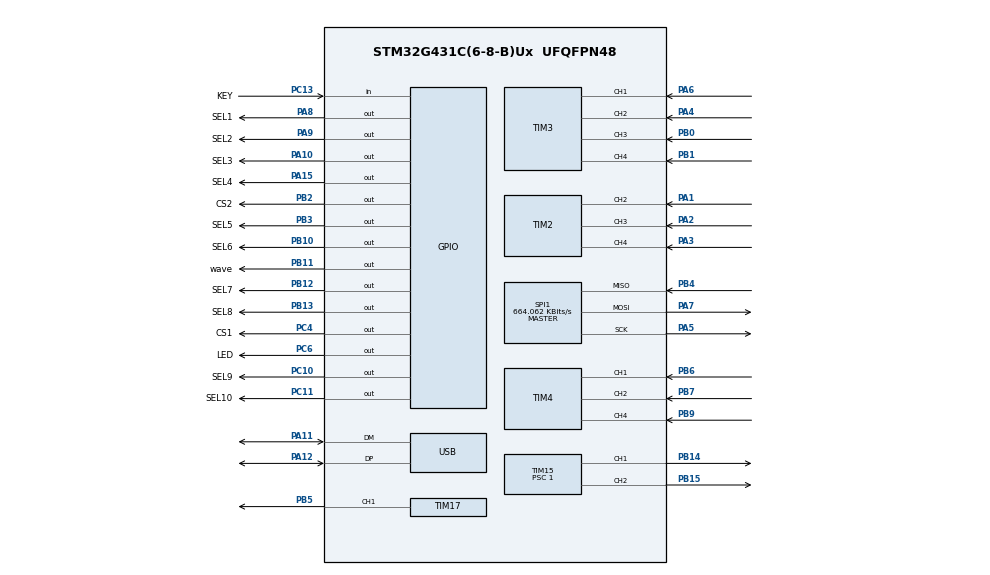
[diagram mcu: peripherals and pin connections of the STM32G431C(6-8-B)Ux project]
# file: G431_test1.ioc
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FREERTOS.BinarySemaphores01=usbBinarySem,Dynamic,NULL
FREERTOS.INCLUDE_uxTaskGetStackHighWaterMark=1
FREERTOS.INCLUDE_vTaskDelayUntil=1
FREERTOS.Queues01=Line1Queue,20,uint16_t,0,Dynamic,NULL,NULL;Line2Queue,20,uint16_t,0,Dynamic,NULL,NULL;Line3Queue,20,uint16_t,0,Dynamic,NULL,NULL;Line4Queue,20,uint16_t,0,Dynamic,NULL,NULL;Line5Queue,20,uint16_t,0,Dynamic,NULL,NULL;Line6Queue,20,uint16_t,0,Dynamic,NULL,NULL;Line7Queue,20,uint16_t,0,Dynamic,NULL,NULL;Line8Queue,100,uint16_t,0,Dynamic,NULL,NULL;Line9Queue,100,uint16_t,0,Dynamic,NULL,NULL;Line10Queue,100,uint16_t,0,Dynamic,NULL,NULL
FREERTOS.Tasks01=defaultTask,0,1024,StartDefaultTask,Default,NULL,Dynamic,NULL,NULL;notifyTask,3,128,NotifyTask,Default,NULL,Dynamic,NULL,NULL;dataTask,-1,128,DataTask,Default,NULL,Dynamic,NULL,NULL
FREERTOS.configTOTAL_HEAP_SIZE=10240
Mcu.Family=STM32G4
Mcu.Name=STM32G431C(6-8-B)Ux
Mcu.Package=UFQFPN48
NVIC.PriorityGroup=NVIC_PRIORITYGROUP_4
NVIC.TIM2_IRQn=true\:5\:0\:false\:true\:false\:4\:true\:true\:false\:true
NVIC.TIM3_IRQn=true\:5\:0\:false\:true\:false\:3\:true\:true\:false\:true
NVIC.TIM4_IRQn=true\:5\:0\:false\:true\:false\:2\:true\:true\:false\:true
NVIC.TIM6_DAC_IRQn=true\:15\:0\:false\:false\:true\:false\:false\:true\:true
NVIC.TIM7_IRQn=true\:5\:0\:true\:true\:false\:1\:true\:true\:false\:true
NVIC.TimeBase=TIM6_DAC_IRQn
NVIC.TimeBaseIP=TIM6
NVIC.USB_LP_IRQn=true\:5\:0\:false\:false\:true\:true\:false\:true\:true
PA1.GPIO_PuPd=GPIO_PULLUP
PA1.GPIO_Speed=GPIO_SPEED_FREQ_VERY_HIGH
PA1.Signal=S_TIM2_CH2
PA10.GPIO_Label=SEL3
PA10.GPIO_ModeDefaultOutputPP=GPIO_MODE_OUTPUT_PP
PA10.GPIO_PuPd=GPIO_PULLUP
PA10.GPIO_Speed=GPIO_SPEED_FREQ_VERY_HIGH
PA10.PinState=GPIO_PIN_SET
PA10.Signal=GPIO_Output
PA11.Mode=Device
PA11.Signal=USB_DM
PA12.Mode=Device
PA12.Signal=USB_DP
PA13.Mode=Serial_Wire
PA13.Signal=SYS_JTMS-SWDIO
PA14.Mode=Serial_Wire
PA14.Signal=SYS_JTCK-SWCLK
PA15.GPIO_Label=SEL4
PA15.GPIO_ModeDefaultOutputPP=GPIO_MODE_OUTPUT_PP
PA15.GPIO_PuPd=GPIO_PULLUP
PA15.GPIO_Speed=GPIO_SPEED_FREQ_VERY_HIGH
PA15.PinState=GPIO_PIN_SET
PA15.Signal=GPIO_Output
PA2.GPIO_PuPd=GPIO_PULLUP
PA2.GPIO_Speed=GPIO_SPEED_FREQ_VERY_HIGH
PA2.Signal=S_TIM2_CH3
PA3.GPIO_PuPd=GPIO_PULLUP
PA3.GPIO_Speed=GPIO_SPEED_FREQ_VERY_HIGH
PA3.Signal=S_TIM2_CH4
PA4.GPIO_PuPd=GPIO_PULLUP
PA4.GPIO_Speed=GPIO_SPEED_FREQ_VERY_HIGH
PA4.Signal=S_TIM3_CH2
PA5.Mode=Full_Duplex_Master
PA5.Signal=SPI1_SCK
PA6.GPIO_PuPd=GPIO_PULLUP
PA6.GPIO_Speed=GPIO_SPEED_FREQ_VERY_HIGH
PA6.Signal=S_TIM3_CH1
PA7.Mode=Full_Duplex_Master
PA7.Signal=SPI1_MOSI
PA8.GPIO_Label=SEL1
PA8.GPIO_ModeDefaultOutputPP=GPIO_MODE_OUTPUT_PP
PA8.GPIO_PuPd=GPIO_PULLUP
PA8.GPIO_Speed=GPIO_SPEED_FREQ_VERY_HIGH
PA8.PinState=GPIO_PIN_SET
PA8.Signal=GPIO_Output
PA9.GPIO_Label=SEL2
PA9.GPIO_ModeDefaultOutputPP=GPIO_MODE_OUTPUT_PP
PA9.GPIO_PuPd=GPIO_PULLUP
PA9.GPIO_Speed=GPIO_SPEED_FREQ_VERY_HIGH
PA9.PinState=GPIO_PIN_SET
PA9.Signal=GPIO_Output
PB0.GPIO_PuPd=GPIO_PULLUP
PB0.GPIO_Speed=GPIO_SPEED_FREQ_VERY_HIGH
PB0.Signal=S_TIM3_CH3
PB1.GPIO_PuPd=GPIO_PULLUP
PB1.GPIO_Speed=GPIO_SPEED_FREQ_VERY_HIGH
PB1.Signal=S_TIM3_CH4
PB10.GPIO_Label=SEL6
PB10.GPIO_ModeDefaultOutputPP=GPIO_MODE_OUTPUT_PP
PB10.GPIO_PuPd=GPIO_PULLUP
PB10.GPIO_Speed=GPIO_SPEED_FREQ_VERY_HIGH
PB10.PinState=GPIO_PIN_SET
PB10.Signal=GPIO_Output
PB11.GPIO_Label=wave
PB11.GPIO_PuPd=GPIO_PULLDOWN
PB11.GPIO_Speed=GPIO_SPEED_FREQ_VERY_HIGH
PB11.Signal=GPIO_Output
PB12.GPIO_Label=SEL7
PB12.GPIO_ModeDefaultOutputPP=GPIO_MODE_OUTPUT_PP
PB12.GPIO_PuPd=GPIO_PULLUP
PB12.GPIO_Speed=GPIO_SPEED_FREQ_VERY_HIGH
PB12.PinState=GPIO_PIN_SET
PB12.Signal=GPIO_Output
PB13.GPIO_Label=SEL8
PB13.GPIO_ModeDefaultOutputPP=GPIO_MODE_OUTPUT_PP
PB13.GPIO_PuPd=GPIO_PULLUP
PB13.GPIO_Speed=GPIO_SPEED_FREQ_VERY_HIGH
PB13.PinState=GPIO_PIN_SET
PB13.Signal=GPIO_Output
PB14.GPIO_PuPd=GPIO_PULLUP
PB14.GPIO_Speed=GPIO_SPEED_FREQ_VERY_HIGH
PB14.Signal=S_TIM15_CH1
PB15.Signal=S_TIM15_CH2
PB2.GPIO_Label=CS2
PB2.GPIO_PuPd=GPIO_PULLUP
PB2.GPIO_Speed=GPIO_SPEED_FREQ_VERY_HIGH
PB2.PinState=GPIO_PIN_SET
PB2.Signal=GPIO_Output
PB3.GPIO_Label=SEL5
PB3.GPIO_ModeDefaultOutputPP=GPIO_MODE_OUTPUT_PP
PB3.GPIO_PuPd=GPIO_PULLUP
PB3.GPIO_Speed=GPIO_SPEED_FREQ_VERY_HIGH
PB3.PinState=GPIO_PIN_SET
PB3.Signal=GPIO_Output
PB4.Mode=Full_Duplex_Master
PB4.Signal=SPI1_MISO
PB5.GPIO_PuPd=GPIO_NOPULL
PB5.GPIO_Speed=GPIO_SPEED_FREQ_VERY_HIGH
PB5.Signal=S_TIM17_CH1
PB6.GPIO_PuPd=GPIO_PULLUP
PB6.GPIO_Speed=GPIO_SPEED_FREQ_VERY_HIGH
PB6.Signal=S_TIM4_CH1
PB7.GPIO_PuPd=GPIO_PULLUP
PB7.GPIO_Speed=GPIO_SPEED_FREQ_VERY_HIGH
PB7.Signal=S_TIM4_CH2
PB9.GPIO_PuPd=GPIO_PULLUP
PB9.GPIO_Speed=GPIO_SPEED_FREQ_VERY_HIGH
PB9.Signal=S_TIM4_CH4
PC10.GPIO_Label=SEL9
PC10.GPIO_ModeDefaultOutputPP=GPIO_MODE_OUTPUT_PP
PC10.GPIO_PuPd=GPIO_PULLUP
PC10.GPIO_Speed=GPIO_SPEED_FREQ_VERY_HIGH
PC10.PinState=GPIO_PIN_SET
PC10.Signal=GPIO_Output
PC11.GPIO_Label=SEL10
PC11.GPIO_ModeDefaultOutputPP=GPIO_MODE_OUTPUT_PP
PC11.GPIO_PuPd=GPIO_PULLUP
PC11.GPIO_Speed=GPIO_SPEED_FREQ_VERY_HIGH
PC11.PinState=GPIO_PIN_SET
PC11.Signal=GPIO_Output
PC13.GPIO_Label=KEY
PC13.GPIO_PuPd=GPIO_PULLDOWN
PC13.Signal=GPIO_Input
PC4.GPIO_Label=CS1
PC4.GPIO_PuPd=GPIO_PULLUP
PC4.GPIO_Speed=GPIO_SPEED_FREQ_VERY_HIGH
PC4.PinState=GPIO_PIN_SET
PC4.Signal=GPIO_Output
PC6.GPIO_Label=LED
PC6.GPIO_PuPd=GPIO_PULLUP
PC6.GPIO_Speed=GPIO_SPEED_FREQ_VERY_HIGH
PC6.PinState=GPIO_PIN_RESET
PC6.Signal=GPIO_Output
PF0-OSC_IN.Mode=HSE-External-Oscillator
PF0-OSC_IN.Signal=RCC_OSC_IN
PF1-OSC_OUT.Mode=HSE-External-Oscillator
PF1-OSC_OUT.Signal=RCC_OSC_OUT
ProjectManager.HeapSize=0x100
ProjectManager.StackSize=0x1000
ProjectManager.TargetToolchain=MDK-ARM V5.32
RCC.ADC12Freq_Value=170000000
RCC.AHBFreq_Value=170000000
RCC.APB1Freq_Value=170000000
RCC.APB1TimFreq_Value=170000000
RCC.APB2Freq_Value=170000000
RCC.APB2TimFreq_Value=170000000
RCC.CK48CLockSelection=RCC_USBCLKSOURCE_HSI48
RCC.CortexFreq_Value=170000000
RCC.EXTERNAL_CLOCK_VALUE=12288000
RCC.HCLKFreq_Value=170000000
RCC.HSE_VALUE=8000000
RCC.HSI48_VALUE=48000000
RCC.HSI_VALUE=16000000
RCC.LSE_VALUE=32768
RCC.PLLM=RCC_PLLM_DIV2
RCC.PLLN=85
RCC.PLLSourceVirtual=RCC_PLLSOURCE_HSE
RCC.SYSCLKFreq_VALUE=170000000
RCC.SYSCLKSource=RCC_SYSCLKSOURCE_PLLCLK
RCC.USBFreq_Value=48000000
RCC.VCOOutputFreq_Value=340000000
SH.S_TIM15_CH1.0=TIM15_CH1,PWM Generation1 CH1
SH.S_TIM15_CH2.0=TIM15_CH2,PWM Generation2 CH2
SH.S_TIM17_CH1.0=TIM17_CH1,PWM Generation1 CH1
SH.S_TIM2_CH2.0=TIM2_CH2,Input_Capture2_from_TI2
SH.S_TIM2_CH3.0=TIM2_CH3,Input_Capture3_from_TI3
SH.S_TIM2_CH4.0=TIM2_CH4,Input_Capture4_from_TI4
SH.S_TIM3_CH1.0=TIM3_CH1,Input_Capture1_from_TI1
SH.S_TIM3_CH2.0=TIM3_CH2,Input_Capture2_from_TI2
SH.S_TIM3_CH3.0=TIM3_CH3,Input_Capture3_from_TI3
SH.S_TIM3_CH4.0=TIM3_CH4,Input_Capture4_from_TI4
SH.S_TIM4_CH1.0=TIM4_CH1,Input_Capture1_from_TI1
SH.S_TIM4_CH2.0=TIM4_CH2,Input_Capture2_from_TI2
SH.S_TIM4_CH4.0=TIM4_CH4,Input_Capture4_from_TI4
SPI1.BaudRatePrescaler=SPI_BAUDRATEPRESCALER_256
SPI1.CalculateBaudRate=664.062 KBits/s
SPI1.DataSize=SPI_DATASIZE_8BIT
SPI1.Direction=SPI_DIRECTION_2LINES
SPI1.Mode=SPI_MODE_MASTER
SPI1.VirtualType=VM_MASTER
TIM15.Channel-PWM\ Generation1\ CH1=TIM_CHANNEL_1
TIM15.Channel-PWM\ Generation2\ CH2=TIM_CHANNEL_2
TIM15.OCPolarity_1=TIM_OCPOLARITY_LOW
TIM15.OCPolarity_2=TIM_OCPOLARITY_LOW
TIM15.PeriodNoDither=9999
TIM15.Prescaler=1
TIM17.Channel=TIM_CHANNEL_1
TIM17.OCIdleState_1=TIM_OCIDLESTATE_SET
TIM17.OCPolarity_1=TIM_OCPOLARITY_HIGH
TIM17.PeriodNoDither=4999
TIM17.Prescaler=1
TIM17.PulseNoDither_1=450
TIM2.Channel-Input_Capture2_from_TI2=TIM_CHANNEL_2
TIM2.Channel-Input_Capture3_from_TI3=TIM_CHANNEL_3
TIM2.Channel-Input_Capture4_from_TI4=TIM_CHANNEL_4
TIM2.ICFilter_CH2=2
TIM2.ICFilter_CH3=2
TIM2.ICFilter_CH4=2
TIM2.ICPolarity_CH2=TIM_INPUTCHANNELPOLARITY_FALLING
TIM2.ICPolarity_CH3=TIM_INPUTCHANNELPOLARITY_FALLING
TIM2.ICPolarity_CH4=TIM_INPUTCHANNELPOLARITY_FALLING
TIM3.Channel-Input_Capture1_from_TI1=TIM_CHANNEL_1
TIM3.Channel-Input_Capture2_from_TI2=TIM_CHANNEL_2
TIM3.Channel-Input_Capture3_from_TI3=TIM_CHANNEL_3
TIM3.Channel-Input_Capture4_from_TI4=TIM_CHANNEL_4
TIM3.ICFilter_CH1=2
TIM3.ICFilter_CH2=2
TIM3.ICFilter_CH3=2
TIM3.ICFilter_CH4=2
TIM3.ICPolarity_CH1=TIM_INPUTCHANNELPOLARITY_FALLING
TIM3.ICPolarity_CH2=TIM_INPUTCHANNELPOLARITY_FALLING
TIM3.ICPolarity_CH3=TIM_INPUTCHANNELPOLARITY_FALLING
TIM3.ICPolarity_CH4=TIM_INPUTCHANNELPOLARITY_FALLING
TIM4.Channel-Input_Capture1_from_TI1=TIM_CHANNEL_1
TIM4.Channel-Input_Capture2_from_TI2=TIM_CHANNEL_2
TIM4.Channel-Input_Capture4_from_TI4=TIM_CHANNEL_4
TIM4.ICFilter_CH1=2
TIM4.ICFilter_CH2=2
TIM4.ICFilter_CH4=2
TIM4.ICPolarity_CH1=TIM_INPUTCHANNELPOLARITY_FALLING
TIM4.ICPolarity_CH2=TIM_INPUTCHANNELPOLARITY_FALLING
TIM4.ICPolarity_CH4=TIM_INPUTCHANNELPOLARITY_FALLING
TIM7.PeriodNoDither=65535
TIM7.Prescaler=199
USB_DEVICE.CLASS_NAME_FS=CDC
USB_DEVICE.VirtualMode=Cdc
USB_DEVICE.VirtualModeFS=Cdc_FS
VP_FREERTOS_VS_CMSIS_V1.Mode=CMSIS_V1
VP_SYS_VS_DBSignals.Mode=DisableDeadBatterySignals
VP_SYS_VS_tim6.Mode=TIM6
VP_TIM17_VS_ClockSourceINT.Mode=Enable_Timer
VP_TIM17_VS_OPM.Mode=OPM_bit
VP_TIM7_VS_ClockSourceINT.Mode=Enable_Timer
VP_USB_DEVICE_VS_USB_DEVICE_CDC_FS.Mode=CDC_FS
board=custom

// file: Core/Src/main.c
/* USER CODE BEGIN Header */
/**
  ******************************************************************************
  * @file           : main.c
  * @brief          : Main program body
  ******************************************************************************
  * @attention
  *
  * Copyright (c) 2024 STMicroelectronics.
  * All rights reserved.
  *
  * This software is licensed under terms that can be found in the LICENSE file
  * in the root directory of this software component.
  * If no LICENSE file comes with this software, it is provided AS-IS.
  *
  ******************************************************************************
  */
/* USER CODE END Header */
#include "main.h"
#include "cmsis_os.h"
#include "spi.h"
#include "tim.h"
#include "usb_device.h"
#include "gpio.h"

void SystemClock_Config(void);
void MX_FREERTOS_Init(void);
static void MX_NVIC_Init(void);

int main(void)
{

  /* MCU Configuration--------------------------------------------------------*/

  /* Reset of all peripherals, Initializes the Flash interface and the Systick. */
  HAL_Init();

  /* Configure the system clock */
  SystemClock_Config();

  /* Initialize all configured peripherals */
  MX_GPIO_Init();
  MX_USB_Device_Init();
  MX_TIM7_Init();
  MX_TIM2_Init();
  MX_TIM3_Init();
  MX_TIM4_Init();
  MX_SPI1_Init();
  MX_TIM15_Init();
  MX_TIM17_Init();

  /* Initialize interrupts */
  MX_NVIC_Init();
  /* USER CODE BEGIN 2 */
	LL_TIM_EnableIT_UPDATE(TIM7);//start TIM7 IRQ
	LL_TIM_EnableCounter(TIM7);//start TIM7

	LL_TIM_EnableIT_UPDATE(TIM3);
	LL_TIM_EnableIT_CC1(TIM3);
	LL_TIM_EnableIT_CC2(TIM3);
	LL_TIM_EnableIT_CC3(TIM3);
	LL_TIM_EnableIT_CC4(TIM3);
	LL_TIM_CC_EnableChannel(TIM3,LL_TIM_CHANNEL_CH1);
	LL_TIM_CC_EnableChannel(TIM3,LL_TIM_CHANNEL_CH2);
	LL_TIM_CC_EnableChannel(TIM3,LL_TIM_CHANNEL_CH3);
	LL_TIM_CC_EnableChannel(TIM3,LL_TIM_CHANNEL_CH4);
	LL_TIM_EnableCounter(TIM3);

	LL_TIM_EnableIT_UPDATE(TIM4);
	LL_TIM_EnableIT_CC1(TIM4);
	LL_TIM_EnableIT_CC2(TIM4);
	LL_TIM_EnableIT_CC4(TIM4);
	LL_TIM_CC_EnableChannel(TIM4,LL_TIM_CHANNEL_CH1);
	LL_TIM_CC_EnableChannel(TIM4,LL_TIM_CHANNEL_CH2);
	LL_TIM_CC_EnableChannel(TIM4,LL_TIM_CHANNEL_CH4);
	LL_TIM_EnableCounter(TIM4);

	LL_TIM_EnableIT_UPDATE(TIM2);
	LL_TIM_EnableIT_CC2(TIM2);
	LL_TIM_EnableIT_CC3(TIM2);
	LL_TIM_EnableIT_CC4(TIM2);
	LL_TIM_CC_EnableChannel(TIM2,LL_TIM_CHANNEL_CH2);
	LL_TIM_CC_EnableChannel(TIM2,LL_TIM_CHANNEL_CH3);
	LL_TIM_CC_EnableChannel(TIM2,LL_TIM_CHANNEL_CH4);
	LL_TIM_EnableCounter(TIM2);

//		LL_GPIO_SetOutputPin(SEL1_GPIO_Port,SEL1_Pin);
//		LL_GPIO_ResetOutputPin(SEL1_GPIO_Port,SEL1_Pin);
  /* USER CODE END 2 */

  /* Call init function for freertos objects (in freertos.c) */
  MX_FREERTOS_Init();

  /* Start scheduler */
  osKernelStart();

  /* We should never get here as control is now taken by the scheduler */
  /* Infinite loop */
  while (1)
  {

  }
}

void SystemClock_Config(void)
{
  RCC_OscInitTypeDef RCC_OscInitStruct = {0};
  RCC_ClkInitTypeDef RCC_ClkInitStruct = {0};

  /** Configure the main internal regulator output voltage
  */
  HAL_PWREx_ControlVoltageScaling(PWR_REGULATOR_VOLTAGE_SCALE1_BOOST);

  /** Initializes the RCC Oscillators according to the specified parameters
  * in the RCC_OscInitTypeDef structure.
  */
  RCC_OscInitStruct.OscillatorType = RCC_OSCILLATORTYPE_HSI48|RCC_OSCILLATORTYPE_HSE;
  RCC_OscInitStruct.HSEState = RCC_HSE_ON;
  RCC_OscInitStruct.HSI48State = RCC_HSI48_ON;
  RCC_OscInitStruct.PLL.PLLState = RCC_PLL_ON;
  RCC_OscInitStruct.PLL.PLLSource = RCC_PLLSOURCE_HSE;
  RCC_OscInitStruct.PLL.PLLM = RCC_PLLM_DIV2;
  RCC_OscInitStruct.PLL.PLLN = 100;
  RCC_OscInitStruct.PLL.PLLP = RCC_PLLP_DIV2;
  RCC_OscInitStruct.PLL.PLLQ = RCC_PLLQ_DIV2;
  RCC_OscInitStruct.PLL.PLLR = RCC_PLLR_DIV2;
  if (HAL_RCC_OscConfig(&RCC_OscInitStruct) != HAL_OK)
  {
    Error_Handler();
  }

  /** Initializes the CPU, AHB and APB buses clocks
  */
  RCC_ClkInitStruct.ClockType = RCC_CLOCKTYPE_HCLK|RCC_CLOCKTYPE_SYSCLK
                              |RCC_CLOCKTYPE_PCLK1|RCC_CLOCKTYPE_PCLK2;
  RCC_ClkInitStruct.SYSCLKSource = RCC_SYSCLKSOURCE_PLLCLK;
  RCC_ClkInitStruct.AHBCLKDivider = RCC_SYSCLK_DIV1;
  RCC_ClkInitStruct.APB1CLKDivider = RCC_HCLK_DIV1;
  RCC_ClkInitStruct.APB2CLKDivider = RCC_HCLK_DIV1;

  if (HAL_RCC_ClockConfig(&RCC_ClkInitStruct, FLASH_LATENCY_4) != HAL_OK)
  {
    Error_Handler();
  }
}

/**
  * @brief NVIC Configuration.
  * @retval None
  */
static void MX_NVIC_Init(void)
{
  /* TIM7_IRQn interrupt configuration */
  NVIC_SetPriority(TIM7_IRQn, NVIC_EncodePriority(NVIC_GetPriorityGrouping(),5, 0));
  NVIC_EnableIRQ(TIM7_IRQn);
  /* TIM4_IRQn interrupt configuration */
  NVIC_SetPriority(TIM4_IRQn, NVIC_EncodePriority(NVIC_GetPriorityGrouping(),5, 0));
  NVIC_EnableIRQ(TIM4_IRQn);
  /* TIM3_IRQn interrupt configuration */
  NVIC_SetPriority(TIM3_IRQn, NVIC_EncodePriority(NVIC_GetPriorityGrouping(),5, 0));
  NVIC_EnableIRQ(TIM3_IRQn);
  /* TIM2_IRQn interrupt configuration */
  NVIC_SetPriority(TIM2_IRQn, NVIC_EncodePriority(NVIC_GetPriorityGrouping(),5, 0));
  NVIC_EnableIRQ(TIM2_IRQn);
}

void HAL_TIM_PeriodElapsedCallback(TIM_HandleTypeDef *htim)
{
  if (htim->Instance == TIM6) {
    HAL_IncTick();
  }
}

void Error_Handler(void)
{
  __disable_irq();
  while (1)
  {
  }
}

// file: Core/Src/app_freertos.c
/* USER CODE BEGIN Header */
/**
  ******************************************************************************
  * File Name          : app_freertos.c
  * Description        : Code for freertos applications
  ******************************************************************************
  * @attention
  *
  * Copyright (c) 2024 STMicroelectronics.
  * All rights reserved.
  *
  * This software is licensed under terms that can be found in the LICENSE file
  * in the root directory of this software component.
  * If no LICENSE file comes with this software, it is provided AS-IS.
  *
  ******************************************************************************
  */
/* USER CODE END Header */

#include "FreeRTOS.h"
#include "task.h"
#include "main.h"
#include "cmsis_os.h"

osThreadId defaultTaskHandle;
osThreadId notifyTaskHandle;
osThreadId dataTaskHandle;
osMessageQId Line1QueueHandle;
osMessageQId Line2QueueHandle;
osMessageQId Line3QueueHandle;
osMessageQId Line4QueueHandle;
osMessageQId Line5QueueHandle;
osMessageQId Line6QueueHandle;
osMessageQId Line7QueueHandle;
osMessageQId Line8QueueHandle;
osMessageQId Line9QueueHandle;
osMessageQId Line10QueueHandle;
osSemaphoreId usbBinarySemHandle;

/* USER CODE BEGIN FunctionPrototypes */
void user_delaynus_tim(uint32_t nus)
{
    uint16_t differ = 0xFFFF - nus - 5;

    // Enable TIM7 peripheral clock
    LL_APB1_GRP1_EnableClock(LL_APB1_GRP1_PERIPH_TIM7);

    // Set the timer counter value
    LL_TIM_SetCounter(TIM7, differ);

    // Configure the timer prescaler if needed (assuming default prescaler 0)
    // LL_TIM_SetPrescaler(TIM7, prescaler_value);

    // Enable the timer
    LL_TIM_EnableCounter(TIM7);

    // Wait until the timer reaches the target value
    while (LL_TIM_GetCounter(TIM7) < 0xFFFF - 5)
    {
        // Optionally, add a timeout condition here to avoid an infinite loop
    }

    // Disable the timer
    LL_TIM_DisableCounter(TIM7);

    // Optionally, disable the TIM7 peripheral clock when done (if no longer needed)
    // LL_APB1_GRP1_DisableClock(LL_APB1_GRP1_PERIPH_TIM7);
}
void ll_Start_TIM17_OnePulse(uint16_t ccr)
{
//	LL_TIM_CC_EnableChannel(TIM17, LL_TIM_CHANNEL_CH1);  // 启用 CH1 输出比较
//	LL_TIM_OC_EnablePreload(TIM17, LL_TIM_CHANNEL_CH1);  // 启用预装载
//	LL_TIM_EnableCounter(TIM17);  // 启动计数器
//	LL_TIM_EnableAllOutputs(TIM17);  // 启用主输出信号   OK可用

	TIM17->CCR1 = 4999-ccr;
	// 启用 TIM17 CH1 输出比较通道
	TIM17->CCER |= TIM_CCER_CC1E;  // 设置 CC1E (Channel 1 Output Enable)
	// 启用 TIM17 CH1 输出比较预装载功能
	TIM17->CCMR1 |= TIM_CCMR1_OC1PE;  // 设置 OC1PE (Output Compare Preload Enable)
	// 启动定时器 TIM17
	TIM17->CR1 |= TIM_CR1_CEN;  // 设置 CEN (Counter Enable) 位
	// 启用 TIM17 主输出信号
	TIM17->BDTR |= TIM_BDTR_MOE;  // 设置 MOE (Main Output Enable) 位

}
//切换列选  把上一个列的引脚置高电平 当前列置低电平
void Select_switcher(uint8_t index)
{
	switch(index)
	{
		case 1:
			SEL10_GPIO_Port->BSRR=SEL10_pin_HIGH;//高电平
			SEL1_GPIO_Port->BSRR=SEL1_pin_LOW;//低电平
			break;
		case 2:
			SEL1_GPIO_Port->BSRR=SEL1_pin_HIGH;//高电平
			SEL2_GPIO_Port->BSRR=SEL2_pin_LOW;//低电平
			break;
		case 3:
			SEL2_GPIO_Port->BSRR=SEL2_pin_HIGH;//高电平
			SEL3_GPIO_Port->BSRR=SEL3_pin_LOW;//低电平
			break;
		case 4:
			SEL3_GPIO_Port->BSRR=SEL3_pin_HIGH;//高电平
			SEL4_GPIO_Port->BSRR=SEL4_pin_LOW;//低电平
			break;
		case 5:
			SEL4_GPIO_Port->BSRR=SEL4_pin_HIGH;//高电平
			SEL5_GPIO_Port->BSRR=SEL5_pin_LOW;//低电平
			break;
		case 6:
			SEL5_GPIO_Port->BSRR=SEL5_pin_HIGH;//高电平
			SEL6_GPIO_Port->BSRR=SEL6_pin_LOW;//低电平
			break;
		case 7:
			SEL6_GPIO_Port->BSRR=SEL6_pin_HIGH;//高电平
			SEL7_GPIO_Port->BSRR=SEL7_pin_LOW;//低电平
			break;
		case 8:
			SEL7_GPIO_Port->BSRR=SEL7_pin_HIGH;//高电平
			SEL8_GPIO_Port->BSRR=SEL8_pin_LOW;//低电平
			break;
		case 9:
			SEL8_GPIO_Port->BSRR=SEL8_pin_HIGH;//高电平
			SEL9_GPIO_Port->BSRR=SEL9_pin_LOW;//低电平
			break;
		case 10:
			SEL9_GPIO_Port->BSRR=SEL9_pin_HIGH;//高电平
			SEL10_GPIO_Port->BSRR=SEL10_pin_LOW;//低电平
			break;
	}
}
/* USER CODE END FunctionPrototypes */

void StartDefaultTask(void const * argument);
void NotifyTask(void const * argument);
void DataTask(void const * argument);

void MX_FREERTOS_Init(void); /* (MISRA C 2004 rule 8.1) */

void MX_FREERTOS_Init(void) {

  /* Create the semaphores(s) */
  /* definition and creation of usbBinarySem */
  osSemaphoreDef(usbBinarySem);
  usbBinarySemHandle = osSemaphoreCreate(osSemaphore(usbBinarySem), 1);

  /* Create the queue(s) */
  /* definition and creation of Line1Queue */
  osMessageQDef(Line1Queue, 20, uint16_t);
  Line1QueueHandle = osMessageCreate(osMessageQ(Line1Queue), NULL);

  /* definition and creation of Line2Queue */
  osMessageQDef(Line2Queue, 20, uint16_t);
  Line2QueueHandle = osMessageCreate(osMessageQ(Line2Queue), NULL);

  /* definition and creation of Line3Queue */
  osMessageQDef(Line3Queue, 20, uint16_t);
  Line3QueueHandle = osMessageCreate(osMessageQ(Line3Queue), NULL);

  /* definition and creation of Line4Queue */
  osMessageQDef(Line4Queue, 20, uint16_t);
  Line4QueueHandle = osMessageCreate(osMessageQ(Line4Queue), NULL);

  /* definition and creation of Line5Queue */
  osMessageQDef(Line5Queue, 20, uint16_t);
  Line5QueueHandle = osMessageCreate(osMessageQ(Line5Queue), NULL);

  /* definition and creation of Line6Queue */
  osMessageQDef(Line6Queue, 20, uint16_t);
  Line6QueueHandle = osMessageCreate(osMessageQ(Line6Queue), NULL);

  /* definition and creation of Line7Queue */
  osMessageQDef(Line7Queue, 20, uint16_t);
  Line7QueueHandle = osMessageCreate(osMessageQ(Line7Queue), NULL);

  /* definition and creation of Line8Queue */
  osMessageQDef(Line8Queue, 100, uint16_t);
  Line8QueueHandle = osMessageCreate(osMessageQ(Line8Queue), NULL);

  /* definition and creation of Line9Queue */
  osMessageQDef(Line9Queue, 100, uint16_t);
  Line9QueueHandle = osMessageCreate(osMessageQ(Line9Queue), NULL);

  /* definition and creation of Line10Queue */
  osMessageQDef(Line10Queue, 100, uint16_t);
  Line10QueueHandle = osMessageCreate(osMessageQ(Line10Queue), NULL);

  /* Create the thread(s) */
  /* definition and creation of defaultTask */
  osThreadDef(defaultTask, StartDefaultTask, osPriorityNormal, 0, 1024);
  defaultTaskHandle = osThreadCreate(osThread(defaultTask), NULL);

  /* definition and creation of notifyTask */
  osThreadDef(notifyTask, NotifyTask, osPriorityRealtime, 0, 128);
  notifyTaskHandle = osThreadCreate(osThread(notifyTask), NULL);

  /* definition and creation of dataTask */
  osThreadDef(dataTask, DataTask, osPriorityBelowNormal, 0, 128);
  dataTaskHandle = osThreadCreate(osThread(dataTask), NULL);

}

/* USER CODE BEGIN Header_StartDefaultTask */
/**
  * @brief  Function implementing the defaultTask thread.
  * @param  argument: Not used
  * @retval None
  */
volatile uint16_t resistance[100];
volatile uint16_t current[100];

volatile uint32_t TIM3_base_it_cnt;
volatile Tim_CaptureTypeDef Timer3_ch1_Cap;
volatile Tim_CaptureTypeDef Timer3_ch2_Cap;
volatile Tim_CaptureTypeDef Timer3_ch3_Cap;
volatile Tim_CaptureTypeDef Timer3_ch4_Cap;

volatile uint32_t TIM4_base_it_cnt;
volatile Tim_CaptureTypeDef Timer4_ch1_Cap;
volatile Tim_CaptureTypeDef Timer4_ch2_Cap;
volatile Tim_CaptureTypeDef Timer4_ch3_Cap;
volatile Tim_CaptureTypeDef Timer4_ch4_Cap;

volatile uint32_t TIM2_base_it_cnt;
volatile Tim_CaptureTypeDef Timer2_ch2_Cap;
volatile Tim_CaptureTypeDef Timer2_ch3_Cap;
volatile Tim_CaptureTypeDef Timer2_ch4_Cap;
typedef union  {
    uint16_t word16;         // 16bit
		uint8_t byte[2];       // 8bit   byte[0]:low_8bit   byte[1]:high_8bit     example:  word16=0x5678  byte[0]=0x78 byte[1]=0x56
}Word_union;
Word_union test_union[5];
Word_union head_data[2];
Word_union res_value_buff[100][10];

/* USER CODE END Header_StartDefaultTask */
void StartDefaultTask(void const * argument)
{
  /* USER CODE BEGIN StartDefaultTask */
	//F405:2-999-100-1.7us-70(2843.75Om)   low time about 3.5us
	uint8_t usb_TxBuf[1024];//小心不要超过任务栈大小
	uint8_t resistance_TxBuf[256+4]={0x55,0xaa,0xcc,0xbb};
	uint32_t usb_RxLength=0;
	uint8_t USBD_Result=0;

	uint16_t i=0;
	for(i=0;i<6;i++)
	{
		AD5206_SetResistance(0, i, 12);//12-528 Om
	}
	osDelay(100);
	for(i=0;i<6;i++)
	{
		AD5206_SetResistance(1, i, 12);//12-542 Om
	}
	osDelay(100);

	AD5206_SetResistance(0, 4, 50);//Vramp1
	//            Prescaler-Period-CCR-wave_time-resistance_para    100pf   dc_power_supply: 5.0V
	//Capture_Filter:x
	//G431 200MHz:0-9999-4450(44.5us)-50(about Om)    200MHz cap PWM_low_value:x   cap VO1_1V1:x
	//G431 200MHz:0-9999-2700(27.0us)-30(about Om)    200MHz cap PWM_low_value:x   cap VO1_1V1:x
	osDelay(100);

	AD5206_SetResistance(0, 5, 255);//Vramp2
	//            Prescaler-Period-CCR-wave_time-resistance_para    100pf   usb_power_supply: 4.9V
	//Capture_Filter:15
	//G431 200MHz:0-9999-200(2.0us)-80(about Om)    200MHz cap PWM_low_value:416   cap VO1_1V1:256
	//G431 200MHz:0-9999-300(3.0us)-120(about Om)    200MHz cap PWM_low_value:608   cap VO1_1V1:384
	//G431 200MHz:0-9999-400(4.0us)-160(about Om)    160/80.0*200=400    200MHz cap PWM_low_value:800   cap VO1_1V1:512
	//G431 200MHz:0-9999-637(6.37us)-255(about Om)    255/160.0*400=637.5    200MHz cap PWM_low_value:1280   cap VO1_1V1:832   usb_power_supply: 4.75V
	osDelay(100);

	HAL_TIM_PWM_Start(&htim15,TIM_CHANNEL_1);
	htim15.Instance->CCR1 = 637;//Vramp2
	HAL_TIM_PWM_Start(&htim15,TIM_CHANNEL_2);
	htim15.Instance->CCR2 = 4450;//Vramp1 test 现不用

	uint32_t receivedMessage=0;
	osEvent event;

	uint32_t ulNotificationValue=0;

	/* Infinite loop */
	for(;;)
	{
		//焊接运放芯片注意GND引脚不要虚焊，用特尖表笔对每个焊盘和引脚都测一下有没有焊上
		LL_GPIO_SetOutputPin(LED_GPIO_Port,LED_Pin);

//		SEL1_GPIO_Port->BSRR=SEL1_pin_HIGH;//高电平
//		SEL2_GPIO_Port->BSRR=SEL2_pin_HIGH;//高电平
//		SEL3_GPIO_Port->BSRR=SEL3_pin_HIGH;//高电平
//		SEL4_GPIO_Port->BSRR=SEL4_pin_HIGH;//高电平
//		SEL5_GPIO_Port->BSRR=SEL5_pin_HIGH;//高电平
//		SEL6_GPIO_Port->BSRR=SEL6_pin_HIGH;//高电平
//		SEL7_GPIO_Port->BSRR=SEL7_pin_HIGH;//高电平
//		SEL8_GPIO_Port->BSRR=SEL8_pin_HIGH;//高电平
//		SEL9_GPIO_Port->BSRR=SEL9_pin_HIGH;//高电平
//		SEL10_GPIO_Port->BSRR=SEL10_pin_HIGH;//高电平
		osDelay(100);

		LL_GPIO_ResetOutputPin(LED_GPIO_Port,LED_Pin);

//		SEL1_GPIO_Port->BSRR=SEL1_pin_LOW;//低电平
//		SEL2_GPIO_Port->BSRR=SEL2_pin_LOW;//低电平
//		SEL3_GPIO_Port->BSRR=SEL3_pin_LOW;//低电平
//		SEL4_GPIO_Port->BSRR=SEL4_pin_LOW;//低电平
//		SEL5_GPIO_Port->BSRR=SEL5_pin_LOW;//低电平
//		SEL6_GPIO_Port->BSRR=SEL6_pin_LOW;//低电平
//		SEL7_GPIO_Port->BSRR=SEL7_pin_LOW;//低电平
//		SEL8_GPIO_Port->BSRR=SEL8_pin_LOW;//低电平
//		SEL9_GPIO_Port->BSRR=SEL9_pin_LOW;//低电平
//		SEL10_GPIO_Port->BSRR=SEL10_pin_LOW;//低电平
		osDelay(100);

//		test_union[0].word16 = 0x5678;
//		res_value_buff[0][0].byte[0]='0';
//		res_value_buff[0][0].byte[1]='1';
//		res_value_buff[0][1].byte[0]='2';
//		res_value_buff[0][1].byte[1]='3';
//		res_value_buff[0][2].byte[0]='4';
//		res_value_buff[0][2].byte[1]='5';
//		res_value_buff[0][3].byte[0]='6';
//		res_value_buff[0][3].byte[1]='7';
//		res_value_buff[0][4].byte[0]='8';
//		res_value_buff[0][4].byte[1]='9';
//		res_value_buff[0][5].word16 =0x4241;
//		res_value_buff[0][6].byte[0]='a';
//		res_value_buff[0][6].byte[1]='\n';
//
//		CDC_Transmit_FS(res_value_buff[0][0].byte, 14);
//		osDelay(1);

//		sprintf((char *)usb_TxBuf,"StartDefaultTask!!&res_value_buff[0][0].word16:%p,&res_value_buff[0][0].byte[0]:%p,&head_data[0].byte[0]:%p,&res_value_buff[0][1].word16:%p\r\n",
//			&res_value_buff[0][0].word16,&res_value_buff[0][0].byte[0],&head_data[0].byte[0],&res_value_buff[0][1].word16);
//		usb_RxLength=strlen((char *)usb_TxBuf);
//
//		osSemaphoreWait(usbBinarySemHandle, osWaitForever);
//		do{
//			USBD_Result=CDC_Transmit_FS(usb_TxBuf, usb_RxLength);
//		}while(USBD_Result!=USBD_OK);
////		USBD_Result=CDC_Transmit_FS(usb_TxBuf, usb_RxLength);
////		while(USBD_Result!=USBD_OK)
////		{
////			USBD_Result=CDC_Transmit_FS(usb_TxBuf, usb_RxLength);
////		}
//		osSemaphoreRelease(usbBinarySemHandle);

//		osDelay(10);

//		print char
//		event = osMessageGet(Line1QueueHandle, osWaitForever);
//		receivedMessage = event.value.v;

//		sprintf((char *)usb_TxBuf,"Remaining StartDefaultTask stack space: %lu bytes\n TIM3_base_it_cnt:%u\n Timer3_ch1_Cap.low_time:%d\n Timer3_ch2_Cap.low_time:%d\n Timer3_ch3_Cap.low_time:%d\n Timer3_ch4_Cap.low_time:%d\n\n Timer4_ch1_Cap.low_time:%d\n Timer4_ch2_Cap.low_time:%d\n Timer4_ch4_Cap.low_time:%d\n\n Timer2_ch2_Cap.low_time:%d\n Timer2_ch3_Cap.low_time:%d\n Timer2_ch4_Cap.low_time:%d\n receivedMessage:%u\n Line1QueueHandle addr:%p \n Line2QueueHandle addr:%p \n",
//			uxTaskGetStackHighWaterMark(NULL) * 4,TIM3_base_it_cnt,Timer3_ch1_Cap.low_time,Timer3_ch2_Cap.low_time,Timer3_ch3_Cap.low_time,Timer3_ch4_Cap.low_time,Timer4_ch1_Cap.low_time,Timer4_ch2_Cap.low_time,Timer4_ch4_Cap.low_time,Timer2_ch2_Cap.low_time,Timer2_ch3_Cap.low_time,Timer2_ch4_Cap.low_time,receivedMessage,&Line1QueueHandle,&Line10QueueHandle);

//		//wave show
//		sprintf((char *)usb_TxBuf,"%d,%d,%d,%d,%d,%d,%d,%d,%d,%d\n",  //%u,%u,%u,%u,%u,%u,%u,%u,%u,%u
//			Timer3_ch1_Cap.low_time,Timer3_ch2_Cap.low_time,Timer3_ch3_Cap.low_time,Timer3_ch4_Cap.low_time,Timer4_ch1_Cap.low_time,Timer4_ch2_Cap.low_time,Timer4_ch4_Cap.low_time,Timer2_ch2_Cap.low_time,Timer2_ch3_Cap.low_time,Timer2_ch4_Cap.low_time);

//		usb_RxLength=strlen((char *)usb_TxBuf);
//
//		osSemaphoreWait(usbBinarySemHandle, osWaitForever);
//		USBD_Result=CDC_Transmit_FS(usb_TxBuf, usb_RxLength);
//		while(USBD_Result!=USBD_OK)
//		{
//			USBD_Result=CDC_Transmit_FS(usb_TxBuf, usb_RxLength);
//		}
//		osSemaphoreRelease(usbBinarySemHandle);

//		for(uint8_t i=0;i<10;i++)
//		{
//			ulNotificationValue = ulTaskNotifyTake(pdTRUE, portMAX_DELAY);  // wait for notification value
//			sprintf((char *)usb_TxBuf,"res_value[%2d][0~9]:%u,%u,%u,%u,%u,%u,%u,%u,%u,%u\n",
//				ulNotificationValue,res_value[ulNotificationValue][0],res_value[ulNotificationValue][1],res_value[ulNotificationValue][2],res_value[ulNotificationValue][3],res_value[ulNotificationValue][4],
//				res_value[ulNotificationValue][5],res_value[ulNotificationValue][6],res_value[ulNotificationValue][7],res_value[ulNotificationValue][8],res_value[ulNotificationValue][9]);
//
//			usb_RxLength=strlen((char *)usb_TxBuf);
//
//			osSemaphoreWait(usbBinarySemHandle, osWaitForever);
//			USBD_Result=CDC_Transmit_FS(usb_TxBuf, usb_RxLength);
//			while(USBD_Result!=USBD_OK)
//			{
//				USBD_Result=CDC_Transmit_FS(usb_TxBuf, usb_RxLength);
//			}
//			osSemaphoreRelease(usbBinarySemHandle);
//		}

//		osDelay(10);
	}
  /* USER CODE END StartDefaultTask */
}

/* USER CODE BEGIN Header_NotifyTask */
/**
* @brief Function implementing the notifyTask thread.
* @param argument: Not used
* @retval None
*/

Word_union test_data[1004];
Word_union res_data_1[1004];
Word_union res_data_2[1004];
Word_union* res_send_p=res_data_1;
Word_union* res_store_p=res_data_2;

//电压采集完成之后需要进行缓存切换
void exchange_res_p(void)
{
	static uint8_t state=1;//第一次运行该函数前 采集的数据存到res_data_2   第一次运行该函数后状态变为0，发送的指针指向res_data_1  之后循环往复
	state=!state;

	if(state)
	{
		res_send_p=res_data_1;
		res_store_p=res_data_2;
	}
	else
	{
		res_send_p=res_data_2;
		res_store_p=res_data_1;
	}
}
uint32_t start_time;//定时器7计数变量，1us计数一次
uint32_t time_cnt;
uint32_t current_time;
/* USER CODE END Header_NotifyTask */
void NotifyTask(void const * argument)
{
  /* USER CODE BEGIN NotifyTask */
	uint32_t ulNotificationValue=0;
	osDelay(20);
	uint8_t USBD_Result=0;

	test_data[0].byte[0]=0x55;//帧头
	test_data[0].byte[1]=0xAA;
	test_data[1].byte[0]=0xBB;
	test_data[1].byte[1]=0xCC;
	for(uint16_t i=0;i<1000;i++)
	{
		test_data[2+i].word16=i*2+2;
	}
	test_data[1002].byte[0]=0xAA;//帧尾
	test_data[1002].byte[1]=0x55;
	test_data[1003].byte[0]=0x66;
	test_data[1003].byte[1]=0x77;

	res_data_1[0].byte[0]=0x55;//帧头
	res_data_1[0].byte[1]=0xAA;
	res_data_1[1].byte[0]=0xBB;
	res_data_1[1].byte[1]=0xCC;
	for(uint16_t i=0;i<1000;i++)
	{
//		res_send_p[2+i].word16=i*1+1;
		res_data_1[2+i].word16=i*1+1;
	}
	res_data_1[1002].byte[0]=0xAA;//帧尾
	res_data_1[1002].byte[1]=0x55;
	res_data_1[1003].byte[0]=0x66;
	res_data_1[1003].byte[1]=0x77;

	res_data_2[0].byte[0]=0x55;//帧头
	res_data_2[0].byte[1]=0xAA;
	res_data_2[1].byte[0]=0xBB;
	res_data_2[1].byte[1]=0xCC;
	for(uint16_t i=0;i<1000;i++)
	{
		res_data_2[2+i].word16=i*2+2;
	}
	res_data_2[1002].byte[0]=0xAA;//帧尾
	res_data_2[1002].byte[1]=0x55;
	res_data_2[1003].byte[0]=0x66;
	res_data_2[1003].byte[1]=0x77;
  /* Infinite loop */
  for(;;)
  {
//		start_time=time_cnt;
		ulNotificationValue = ulTaskNotifyTake(pdTRUE, portMAX_DELAY);  // wait for notification value
//		do{
			USBD_Result=CDC_Transmit_FS(res_send_p->byte, 2008);
//		}while(USBD_Result!=USBD_OK);//经过测试 仅运行这个发送函数只需要8us，一次完整的2008字节发送完毕需要2.3ms(433.7帧/秒)

//		current_time=time_cnt;
//		res_send_p[2].word16=(uint16_t)(current_time-start_time);
//		res_send_p[3].word16=(uint16_t)((current_time-start_time)>>16);

//		osDelay(20);

/*
////		ulNotificationValue = ulTaskNotifyTake(pdTRUE, portMAX_DELAY);  // wait for notification value
////
////		if (ulNotificationValue) {// == 0x1234
////						LL_GPIO_TogglePin(GPIOC,GPIO_PIN_6);
//////						osDelay(100);
////        }
//		if(LL_GPIO_IsInputPinSet(GPIOC, LL_GPIO_PIN_13))//按键
//		{
//			osDelay(20);
//			while(LL_GPIO_IsInputPinSet(GPIOC, LL_GPIO_PIN_13));
//			osDelay(20);
//
//			LL_GPIO_SetOutputPin(GPIOB,GPIO_PIN_11);
////			osDelay(1);
//			user_delaynus_tim(3);
//
////			htim17.Instance->CCR1 = 4450;
////			user_delaynus_tim(500);
//
////			ll_Start_TIM17_OnePulse(4450);
////			user_delaynus_tim(50);
//
//			LL_GPIO_ResetOutputPin(GPIOB,GPIO_PIN_11);
//
//		}
//		osDelay(20);
*/
  }
  /* USER CODE END NotifyTask */
}

/* USER CODE BEGIN Header_DataTask */
/**
* @brief Function implementing the dataTask thread.
* @param argument: Not used
* @retval None
*/
//union Flags res_flags;
uint8_t res_flags[10]={0};
/* USER CODE END Header_DataTask */
void DataTask(void const * argument)
{
  /* USER CODE BEGIN DataTask */
  /* Infinite loop */
	uint32_t receivedMessage=0;
	osEvent event[10];
	uint8_t i=0,j=0;

	uint8_t Notify_send_flag=0;
	osDelay(2000);
	TickType_t xLastWakeTime;
	xLastWakeTime = xTaskGetTickCount();
  for(;;)
  {
			for(j=0;j<100;j++)
			{
				Select_switcher(j%10+1);
//				user_delaynus_tim(5);
				ll_Start_TIM17_OnePulse(4450);
				if(!Notify_send_flag)//第一次触发扫描波形后发送通知 数据发送指令的执行时间小于一次扫描
				{
					xTaskNotifyGive(notifyTaskHandle);//发送通知给usb通信任务  这个还是得放在ll_Start_TIM17_OnePulse之后，节约整体时间，在比较器已经开始采集新的一帧时候将上一帧发送出去
					taskYIELD();// 手动触发上下文切换
					Notify_send_flag = 1;
				}

				while(res_flags[0]+res_flags[1]+res_flags[2]+res_flags[3]+res_flags[4]+res_flags[5]+res_flags[6]+res_flags[7]+res_flags[8]+res_flags[9]!=10)
				{
					for(i=0;i<10;i++)
					{
						event[i] = osMessageGet(*(&Line1QueueHandle+i), 0);//osWaitForever
						if (event[i].status == osEventMessage)
						{
							res_store_p[j*10+i+2].word16=event[i].value.v;

//							if(res_store_p==res_data_1)//测试是否根据缓存切换来正确存入数据
//								res_store_p[j*10+i+2].word16=(j*10+i)*5;
//							if(res_store_p==res_data_2)
//								res_store_p[j*10+i+2].word16=(j*10+i)*5+1;

							res_flags[i]=1;
						}
						else
						{

						}
					}
				}
				for(i=0;i<10;i++)res_flags[i]=0;//清除单行/列就绪标志
			}
			//全部10帧数据缓存完毕
			exchange_res_p();//切换缓存区
			Notify_send_flag = 0;

//			xTaskNotifyGive(notifyTaskHandle);
//			xTaskNotifyGive(defaultTaskHandle);
//			xTaskNotify(defaultTaskHandle, j, eSetValueWithOverwrite);
//			vTaskDelayUntil(&xLastWakeTime, pdMS_TO_TICKS(100));
//			taskYIELD();// 手动触发上下文切换
  }
	while(1){osDelay(1000);}
  /* USER CODE END DataTask */
}

/* USER CODE BEGIN Application */
void TIM7_IRQHandler(void)
{
//	static uint16_t cnt=0;
	if (LL_TIM_IsActiveFlag_UPDATE(TIM7))  //check IRQ flag
	{
		LL_TIM_ClearFlag_UPDATE(TIM7);  //clear IRQ flag

		time_cnt++;//原用于1us中断来计时，现不用
//		if(cnt<100)cnt++;
//		else
//		{
//			cnt=0;
//
////			BaseType_t xHigherPriorityTaskWoken = pdFALSE;
//////			xTaskNotifyGive(notifyTaskHandle);//send notification (used in the task!!!)
//////			vTaskNotifyGiveFromISR(notifyTaskHandle, &xHigherPriorityTaskWoken);send notification in IRQ
////			xTaskNotifyFromISR(notifyTaskHandle,0x02,eSetValueWithOverwrite,&xHigherPriorityTaskWoken);//send notification in IRQ with value
////			portYIELD_FROM_ISR(xHigherPriorityTaskWoken);//trigger task switching
//		}

	}
}
void TIM3_IRQHandler(void)
{
	if (LL_TIM_IsActiveFlag_UPDATE(TIM3))  //check IRQ flag
	{
		LL_TIM_ClearFlag_UPDATE(TIM3);  //clear IRQ flag
		TIM3_base_it_cnt++;
//		Timer3_ch1_Cap.OverflowCount++;
//		Timer3_ch2_Cap.OverflowCount++;
//		Timer3_ch3_Cap.OverflowCount++;
//		Timer3_ch4_Cap.OverflowCount++;
	}
	if(LL_TIM_IsActiveFlag_CC1(TIM3))
	{
		LL_TIM_ClearFlag_CC1(TIM3);	//clear CC1 IRQ flag

		switch(Timer3_ch1_Cap.capture_Cnt){
			case 0:
				Timer3_ch1_Cap.capture_Buf[0] = LL_TIM_IC_GetCaptureCH1(TIM3);//获取当前的捕获值.
				Timer3_ch1_Cap.OverflowCount=0;
				LL_TIM_IC_SetPolarity(TIM3,LL_TIM_CHANNEL_CH1,LL_TIM_IC_POLARITY_RISING);  //设置为上升沿捕获
				Timer3_ch1_Cap.capture_Cnt=1;
				break;
			case 1:
				Timer3_ch1_Cap.capture_Buf[1] = LL_TIM_IC_GetCaptureCH1(TIM3);//获取当前的捕获值.
//				Timer3_ch1_Cap.low_time = Timer3_ch1_Cap.capture_Buf[1] - Timer3_ch1_Cap.capture_Buf[0] + ( Timer3_ch1_Cap.OverflowCount << 16 );    //低电平时间
				Timer3_ch1_Cap.low_time = Timer3_ch1_Cap.capture_Buf[1] - Timer3_ch1_Cap.capture_Buf[0];    //低电平时间
				if(Timer3_ch1_Cap.low_time < 0 )Timer3_ch1_Cap.low_time += 0xFFFF;

				LL_TIM_IC_SetPolarity(TIM3,LL_TIM_CHANNEL_CH1,LL_TIM_IC_POLARITY_FALLING);  //设置为下降沿捕获
				Timer3_ch1_Cap.capture_Cnt=0;

				osMessagePut(Line1QueueHandle,(uint16_t)Timer3_ch1_Cap.low_time,0);
//				xReturn[0].status=osMessagePut(tim3ch1QueueHandle,(uint16_t)Timer3_ch1_Cap.low_time,0);
//				//	if(osOK!=xReturn.status)
//				//	{
//				//		while(1);
//				////		printf("send fail\n");
//				//	}

//			BaseType_t xHigherPriorityTaskWoken = pdFALSE;
//    uint32_t message = Timer3_ch1_Cap.low_time;  // 获取计时器值作为消息

//    // 从中断向队列发送消息
//    xQueueSendFromISR(Line1QueueHandle, &message, &xHigherPriorityTaskWoken);

//    // 如果需要，触发上下文切换
//    portYIELD_FROM_ISR(xHigherPriorityTaskWoken);
		}
	}
	if(LL_TIM_IsActiveFlag_CC2(TIM3))
	{
		LL_TIM_ClearFlag_CC2(TIM3);	//clear CC2 IRQ flag

		switch(Timer3_ch2_Cap.capture_Cnt){
			case 0:
				Timer3_ch2_Cap.capture_Buf[0] = LL_TIM_IC_GetCaptureCH2(TIM3);//获取当前的捕获值.
				Timer3_ch2_Cap.OverflowCount=0;
				LL_TIM_IC_SetPolarity(TIM3,LL_TIM_CHANNEL_CH2,LL_TIM_IC_POLARITY_RISING);  //设置为上升沿捕获
				Timer3_ch2_Cap.capture_Cnt=1;
				break;
			case 1:
				Timer3_ch2_Cap.capture_Buf[1] = LL_TIM_IC_GetCaptureCH2(TIM3);//获取当前的捕获值.
//				Timer3_ch2_Cap.low_time = Timer3_ch2_Cap.capture_Buf[1] - Timer3_ch2_Cap.capture_Buf[0] + ( Timer3_ch2_Cap.OverflowCount << 16 );    //低电平时间
				Timer3_ch2_Cap.low_time = Timer3_ch2_Cap.capture_Buf[1] - Timer3_ch2_Cap.capture_Buf[0];    //低电平时间
				if(Timer3_ch2_Cap.low_time < 0 )Timer3_ch2_Cap.low_time += 0xFFFF;

				LL_TIM_IC_SetPolarity(TIM3,LL_TIM_CHANNEL_CH2,LL_TIM_IC_POLARITY_FALLING);  //设置为下降沿捕获
				Timer3_ch2_Cap.capture_Cnt=0;

				osMessagePut(Line2QueueHandle,(uint16_t)Timer3_ch2_Cap.low_time,0);
		}
	}
	if(LL_TIM_IsActiveFlag_CC3(TIM3))
	{
		LL_TIM_ClearFlag_CC3(TIM3);	//clear CC3 IRQ flag

		switch(Timer3_ch3_Cap.capture_Cnt){
			case 0:
				Timer3_ch3_Cap.capture_Buf[0] = LL_TIM_IC_GetCaptureCH3(TIM3);//获取当前的捕获值.
				Timer3_ch3_Cap.OverflowCount=0;
				LL_TIM_IC_SetPolarity(TIM3,LL_TIM_CHANNEL_CH3,LL_TIM_IC_POLARITY_RISING);  //设置为上升沿捕获
				Timer3_ch3_Cap.capture_Cnt=1;
				break;
			case 1:
				Timer3_ch3_Cap.capture_Buf[1] = LL_TIM_IC_GetCaptureCH3(TIM3);//获取当前的捕获值.
//				Timer3_ch3_Cap.low_time = Timer3_ch3_Cap.capture_Buf[1] - Timer3_ch3_Cap.capture_Buf[0] + ( Timer3_ch3_Cap.OverflowCount << 16 );    //低电平时间
				Timer3_ch3_Cap.low_time = Timer3_ch3_Cap.capture_Buf[1] - Timer3_ch3_Cap.capture_Buf[0];    //低电平时间
				if(Timer3_ch3_Cap.low_time < 0 )Timer3_ch3_Cap.low_time += 0xFFFF;

				LL_TIM_IC_SetPolarity(TIM3,LL_TIM_CHANNEL_CH3,LL_TIM_IC_POLARITY_FALLING);  //设置为下降沿捕获
				Timer3_ch3_Cap.capture_Cnt=0;

				osMessagePut(Line3QueueHandle,(uint16_t)Timer3_ch3_Cap.low_time,0);
		}
	}
	if(LL_TIM_IsActiveFlag_CC4(TIM3))
	{
		LL_TIM_ClearFlag_CC4(TIM3);	//clear CC4 IRQ flag

		switch(Timer3_ch4_Cap.capture_Cnt){
			case 0:
				Timer3_ch4_Cap.capture_Buf[0] = LL_TIM_IC_GetCaptureCH4(TIM3);//获取当前的捕获值.
				Timer3_ch4_Cap.OverflowCount=0;
				LL_TIM_IC_SetPolarity(TIM3,LL_TIM_CHANNEL_CH4,LL_TIM_IC_POLARITY_RISING);  //设置为上升沿捕获
				Timer3_ch4_Cap.capture_Cnt=1;
				break;
			case 1:
				Timer3_ch4_Cap.capture_Buf[1] = LL_TIM_IC_GetCaptureCH4(TIM3);//获取当前的捕获值.
//				Timer3_ch4_Cap.low_time = Timer3_ch4_Cap.capture_Buf[1] - Timer3_ch4_Cap.capture_Buf[0] + ( Timer3_ch4_Cap.OverflowCount << 16 );    //低电平时间
				Timer3_ch4_Cap.low_time = Timer3_ch4_Cap.capture_Buf[1] - Timer3_ch4_Cap.capture_Buf[0];    //低电平时间
				if(Timer3_ch4_Cap.low_time < 0 )Timer3_ch4_Cap.low_time += 0xFFFF;

				LL_TIM_IC_SetPolarity(TIM3,LL_TIM_CHANNEL_CH4,LL_TIM_IC_POLARITY_FALLING);  //设置为下降沿捕获
				Timer3_ch4_Cap.capture_Cnt=0;

				osMessagePut(Line4QueueHandle,(uint16_t)Timer3_ch4_Cap.low_time,0);
		}
	}

}

void TIM4_IRQHandler(void)
{
	if (LL_TIM_IsActiveFlag_UPDATE(TIM4))  //check IRQ flag
	{
		LL_TIM_ClearFlag_UPDATE(TIM4);  //clear IRQ flag
		TIM4_base_it_cnt++;
//		Timer4_ch1_Cap.OverflowCount++;
//		Timer4_ch2_Cap.OverflowCount++;
//		Timer4_ch4_Cap.OverflowCount++;
	}
	if(LL_TIM_IsActiveFlag_CC1(TIM4))
	{
		LL_TIM_ClearFlag_CC1(TIM4);	//clear CC1 IRQ flag

		switch(Timer4_ch1_Cap.capture_Cnt){
			case 0:
				Timer4_ch1_Cap.capture_Buf[0] = LL_TIM_IC_GetCaptureCH1(TIM4);//获取当前的捕获值.
				Timer4_ch1_Cap.OverflowCount=0;
				LL_TIM_IC_SetPolarity(TIM4,LL_TIM_CHANNEL_CH1,LL_TIM_IC_POLARITY_RISING);  //设置为上升沿捕获
				Timer4_ch1_Cap.capture_Cnt=1;
				break;
			case 1:
				Timer4_ch1_Cap.capture_Buf[1] = LL_TIM_IC_GetCaptureCH1(TIM4);//获取当前的捕获值.
//				Timer4_ch1_Cap.low_time = Timer4_ch1_Cap.capture_Buf[1] - Timer4_ch1_Cap.capture_Buf[0] + ( Timer4_ch1_Cap.OverflowCount << 16 );    //低电平时间
				Timer4_ch1_Cap.low_time = Timer4_ch1_Cap.capture_Buf[1] - Timer4_ch1_Cap.capture_Buf[0];    //低电平时间
				if(Timer4_ch1_Cap.low_time < 0 )Timer4_ch1_Cap.low_time += 0xFFFF;

				LL_TIM_IC_SetPolarity(TIM4,LL_TIM_CHANNEL_CH1,LL_TIM_IC_POLARITY_FALLING);  //设置为下降沿捕获
				Timer4_ch1_Cap.capture_Cnt=0;

				osMessagePut(Line5QueueHandle,(uint16_t)Timer4_ch1_Cap.low_time,0);
		}
	}
	if(LL_TIM_IsActiveFlag_CC2(TIM4))
	{
		LL_TIM_ClearFlag_CC2(TIM4);	//clear CC2 IRQ flag

		switch(Timer4_ch2_Cap.capture_Cnt){
			case 0:
				Timer4_ch2_Cap.capture_Buf[0] = LL_TIM_IC_GetCaptureCH2(TIM4);//获取当前的捕获值.
				Timer4_ch2_Cap.OverflowCount=0;
				LL_TIM_IC_SetPolarity(TIM4,LL_TIM_CHANNEL_CH2,LL_TIM_IC_POLARITY_RISING);  //设置为上升沿捕获
				Timer4_ch2_Cap.capture_Cnt=1;
				break;
			case 1:
				Timer4_ch2_Cap.capture_Buf[1] = LL_TIM_IC_GetCaptureCH2(TIM4);//获取当前的捕获值.
//				Timer4_ch2_Cap.low_time = Timer4_ch2_Cap.capture_Buf[1] - Timer4_ch2_Cap.capture_Buf[0] + ( Timer4_ch2_Cap.OverflowCount << 16 );    //低电平时间
				Timer4_ch2_Cap.low_time = Timer4_ch2_Cap.capture_Buf[1] - Timer4_ch2_Cap.capture_Buf[0];    //低电平时间
				if(Timer4_ch2_Cap.low_time < 0 )Timer4_ch2_Cap.low_time += 0xFFFF;

				LL_TIM_IC_SetPolarity(TIM4,LL_TIM_CHANNEL_CH2,LL_TIM_IC_POLARITY_FALLING);  //设置为下降沿捕获
				Timer4_ch2_Cap.capture_Cnt=0;

				osMessagePut(Line6QueueHandle,(uint16_t)Timer4_ch2_Cap.low_time,0);
		}
	}
	if(LL_TIM_IsActiveFlag_CC4(TIM4))
	{
		LL_TIM_ClearFlag_CC4(TIM4);	//clear CC4 IRQ flag

		switch(Timer4_ch4_Cap.capture_Cnt){
			case 0:
				Timer4_ch4_Cap.capture_Buf[0] = LL_TIM_IC_GetCaptureCH4(TIM4);//获取当前的捕获值.
				Timer4_ch4_Cap.OverflowCount=0;
				LL_TIM_IC_SetPolarity(TIM4,LL_TIM_CHANNEL_CH4,LL_TIM_IC_POLARITY_RISING);  //设置为上升沿捕获
				Timer4_ch4_Cap.capture_Cnt=1;
				break;
			case 1:
				Timer4_ch4_Cap.capture_Buf[1] = LL_TIM_IC_GetCaptureCH4(TIM4);//获取当前的捕获值.
				Timer4_ch4_Cap.low_time = Timer4_ch4_Cap.capture_Buf[1] - Timer4_ch4_Cap.capture_Buf[0] + ( Timer4_ch4_Cap.OverflowCount << 16 );    //低电平时间
				Timer4_ch4_Cap.low_time = Timer4_ch4_Cap.capture_Buf[1] - Timer4_ch4_Cap.capture_Buf[0];    //低电平时间
				if(Timer4_ch4_Cap.low_time < 0 )Timer4_ch4_Cap.low_time += 0xFFFF;

				LL_TIM_IC_SetPolarity(TIM4,LL_TIM_CHANNEL_CH4,LL_TIM_IC_POLARITY_FALLING);  //设置为下降沿捕获
				Timer4_ch4_Cap.capture_Cnt=0;

				osMessagePut(Line7QueueHandle,(uint16_t)Timer4_ch4_Cap.low_time,0);
		}
	}
}

void TIM2_IRQHandler(void)
{
	if (LL_TIM_IsActiveFlag_UPDATE(TIM2))  //check IRQ flag
	{
		LL_TIM_ClearFlag_UPDATE(TIM2);  //clear IRQ flag
		TIM2_base_it_cnt++;
//		Timer2_ch2_Cap.OverflowCount++;
//		Timer2_ch3_Cap.OverflowCount++;
//		Timer2_ch4_Cap.OverflowCount++;
	}
	if(LL_TIM_IsActiveFlag_CC2(TIM2))
	{
		LL_TIM_ClearFlag_CC2(TIM2);	//clear CC2 IRQ flag

		switch(Timer2_ch2_Cap.capture_Cnt){
			case 0:
				Timer2_ch2_Cap.capture_Buf[0] = LL_TIM_IC_GetCaptureCH2(TIM2);//获取当前的捕获值.
				Timer2_ch2_Cap.OverflowCount=0;
				LL_TIM_IC_SetPolarity(TIM2,LL_TIM_CHANNEL_CH2,LL_TIM_IC_POLARITY_RISING);  //设置为上升沿捕获
				Timer2_ch2_Cap.capture_Cnt=1;
				break;
			case 1:
				Timer2_ch2_Cap.capture_Buf[1] = LL_TIM_IC_GetCaptureCH2(TIM2);//获取当前的捕获值.
//				Timer2_ch2_Cap.low_time = Timer2_ch2_Cap.capture_Buf[1] - Timer2_ch2_Cap.capture_Buf[0] + ( Timer2_ch2_Cap.OverflowCount << 16 );    //低电平时间
				Timer2_ch2_Cap.low_time = Timer2_ch2_Cap.capture_Buf[1] - Timer2_ch2_Cap.capture_Buf[0];    //低电平时间
				if(Timer2_ch2_Cap.low_time < 0 )Timer2_ch2_Cap.low_time += 0xFFFFFFFF;

				LL_TIM_IC_SetPolarity(TIM2,LL_TIM_CHANNEL_CH2,LL_TIM_IC_POLARITY_FALLING);  //设置为下降沿捕获
				Timer2_ch2_Cap.capture_Cnt=0;

				osMessagePut(Line8QueueHandle,(uint16_t)Timer2_ch2_Cap.low_time,0);
		}
	}
	if(LL_TIM_IsActiveFlag_CC3(TIM2))
	{
		LL_TIM_ClearFlag_CC3(TIM2);	//clear CC3 IRQ flag

		switch(Timer2_ch3_Cap.capture_Cnt){
			case 0:
				Timer2_ch3_Cap.capture_Buf[0] = LL_TIM_IC_GetCaptureCH3(TIM2);//获取当前的捕获值.
				Timer2_ch3_Cap.OverflowCount=0;
				LL_TIM_IC_SetPolarity(TIM2,LL_TIM_CHANNEL_CH3,LL_TIM_IC_POLARITY_RISING);  //设置为上升沿捕获
				Timer2_ch3_Cap.capture_Cnt=1;
				break;
			case 1:
				Timer2_ch3_Cap.capture_Buf[1] = LL_TIM_IC_GetCaptureCH3(TIM2);//获取当前的捕获值.
				Timer2_ch3_Cap.low_time = Timer2_ch3_Cap.capture_Buf[1] - Timer2_ch3_Cap.capture_Buf[0] + ( Timer2_ch3_Cap.OverflowCount << 16 );    //低电平时间
				Timer2_ch3_Cap.low_time = Timer2_ch3_Cap.capture_Buf[1] - Timer2_ch3_Cap.capture_Buf[0];    //低电平时间
				if(Timer2_ch3_Cap.low_time < 0 )Timer2_ch3_Cap.low_time += 0xFFFFFFFF;

				LL_TIM_IC_SetPolarity(TIM2,LL_TIM_CHANNEL_CH3,LL_TIM_IC_POLARITY_FALLING);  //设置为下降沿捕获
				Timer2_ch3_Cap.capture_Cnt=0;

				osMessagePut(Line9QueueHandle,(uint16_t)Timer2_ch3_Cap.low_time,0);
		}
	}
	if(LL_TIM_IsActiveFlag_CC4(TIM2))
	{
		LL_TIM_ClearFlag_CC4(TIM2);	//clear CC4 IRQ flag

		switch(Timer2_ch4_Cap.capture_Cnt){
			case 0:
				Timer2_ch4_Cap.capture_Buf[0] = LL_TIM_IC_GetCaptureCH4(TIM2);//获取当前的捕获值.
				Timer2_ch4_Cap.OverflowCount=0;
				LL_TIM_IC_SetPolarity(TIM2,LL_TIM_CHANNEL_CH4,LL_TIM_IC_POLARITY_RISING);  //设置为上升沿捕获
				Timer2_ch4_Cap.capture_Cnt=1;
				break;
			case 1:
				Timer2_ch4_Cap.capture_Buf[1] = LL_TIM_IC_GetCaptureCH4(TIM2);//获取当前的捕获值.
				Timer2_ch4_Cap.low_time = Timer2_ch4_Cap.capture_Buf[1] - Timer2_ch4_Cap.capture_Buf[0] + ( Timer2_ch4_Cap.OverflowCount << 16 );    //低电平时间
				Timer2_ch4_Cap.low_time = Timer2_ch4_Cap.capture_Buf[1] - Timer2_ch4_Cap.capture_Buf[0];    //低电平时间
				if(Timer2_ch4_Cap.low_time < 0 )Timer2_ch4_Cap.low_time += 0xFFFFFFFF;

				LL_TIM_IC_SetPolarity(TIM2,LL_TIM_CHANNEL_CH4,LL_TIM_IC_POLARITY_FALLING);  //设置为下降沿捕获
				Timer2_ch4_Cap.capture_Cnt=0;

				osMessagePut(Line10QueueHandle,(uint16_t)Timer2_ch4_Cap.low_time,0);
		}
	}

}

// 设置AD5206的电阻值
void AD5206_SetResistance(uint8_t index, uint8_t channel, uint8_t resistance) {
		uint8_t spi_data[2]={0x00,10};

    // 确保通道和电阻值在有效范围内
    if (channel > 5) return; // AD5206有6个通道，通道号从0到5
    if (resistance > 255) return; // 电阻值应在0到255之间
		if (index!=0 && index!=1) return;

		if(index==0)
			HAL_GPIO_WritePin(CS1_GPIO_Port,CS1_Pin,0);
		else if(index==1)
			HAL_GPIO_WritePin(CS2_GPIO_Port,CS2_Pin,0);

		spi_data[0]=channel;
		spi_data[1]=resistance;

		HAL_SPI_Transmit(&hspi1,spi_data,2,0xffff);
    if(index==0)
			HAL_GPIO_WritePin(CS1_GPIO_Port,CS1_Pin,1);
		else if(index==1)
			HAL_GPIO_WritePin(CS2_GPIO_Port,CS2_Pin,1);
}
/* USER CODE END Application */
